VERSION 5.7 ;
  NOWIREEXTENSIONATPIN ON ;
  DIVIDERCHAR "/" ;
  BUSBITCHARS "[]" ;
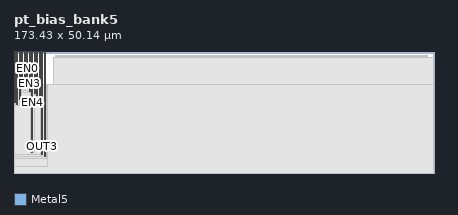
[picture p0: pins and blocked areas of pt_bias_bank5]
MACRO pt_bias_bank5
  CLASS BLOCK ;
  FOREIGN pt_bias_bank5 ;
  ORIGIN -0.300 48.920 ;
  SIZE 173.430 BY 50.140 ;
  PIN VDD
    DIRECTION INOUT ;
    USE POWER ;
    PORT
      LAYER Metal5 ;
        RECT 0.300 -19.620 0.740 1.220 ;
    END
  END VDD
  PIN VSS
    DIRECTION INOUT ;
    USE GROUND ;
    PORT
      LAYER Metal5 ;
        RECT 1.340 -20.520 1.780 1.220 ;
    END
  END VSS
  PIN TRK
    DIRECTION INPUT ;
    USE SIGNAL ;
    ANTENNAGATEAREA 240.000000 ;
    ANTENNADIFFAREA 2.600000 ;
    PORT
      LAYER Metal5 ;
        RECT 2.380 -18.720 2.820 1.220 ;
    END
  END TRK
  PIN EN0
    DIRECTION INPUT ;
    USE SIGNAL ;
    ANTENNAGATEAREA 3.360000 ;
    PORT
      LAYER Metal5 ;
        RECT 3.420 -12.420 3.860 1.220 ;
    END
  END EN0
  PIN EN1
    DIRECTION INPUT ;
    USE SIGNAL ;
    ANTENNAGATEAREA 3.360000 ;
    PORT
      LAYER Metal5 ;
        RECT 4.460 -13.320 4.900 1.220 ;
    END
  END EN1
  PIN EN2
    DIRECTION INPUT ;
    USE SIGNAL ;
    ANTENNAGATEAREA 3.360000 ;
    PORT
      LAYER Metal5 ;
        RECT 5.500 -14.220 5.940 1.220 ;
    END
  END EN2
  PIN EN3
    DIRECTION INPUT ;
    USE SIGNAL ;
    ANTENNAGATEAREA 3.360000 ;
    PORT
      LAYER Metal5 ;
        RECT 6.540 -15.120 6.980 1.220 ;
    END
  END EN3
  PIN EN4
    DIRECTION INPUT ;
    USE SIGNAL ;
    ANTENNAGATEAREA 3.360000 ;
    PORT
      LAYER Metal5 ;
        RECT 7.580 -40.480 8.020 1.220 ;
    END
  END EN4
  PIN OUT0
    DIRECTION OUTPUT ;
    USE SIGNAL ;
    ANTENNADIFFAREA 3.520000 ;
    PORT
      LAYER Metal5 ;
        RECT 8.620 -16.020 9.060 1.220 ;
    END
  END OUT0
  PIN OUT1
    DIRECTION OUTPUT ;
    USE SIGNAL ;
    ANTENNADIFFAREA 3.520000 ;
    PORT
      LAYER Metal5 ;
        RECT 9.660 -16.920 10.100 1.220 ;
    END
  END OUT1
  PIN OUT2
    DIRECTION OUTPUT ;
    USE SIGNAL ;
    ANTENNADIFFAREA 3.520000 ;
    PORT
      LAYER Metal5 ;
        RECT 10.700 -17.820 11.140 1.220 ;
    END
  END OUT2
  PIN OUT3
    DIRECTION OUTPUT ;
    USE SIGNAL ;
    ANTENNADIFFAREA 3.520000 ;
    PORT
      LAYER Metal5 ;
        RECT 11.740 -41.380 12.180 1.220 ;
    END
  END OUT3
  PIN OUT4
    DIRECTION OUTPUT ;
    USE SIGNAL ;
    ANTENNADIFFAREA 3.520000 ;
    PORT
      LAYER Metal5 ;
        RECT 12.780 -42.280 13.220 1.220 ;
    END
  END OUT4
  OBS
      LAYER Nwell ;
        RECT 17.410 -39.220 171.130 -0.600 ;
      LAYER Metal1 ;
        RECT 17.595 -39.120 171.030 -0.785 ;
      LAYER Metal2 ;
        RECT 16.510 -39.120 173.730 -1.360 ;
      LAYER Metal3 ;
        RECT 16.510 -48.920 173.730 -1.360 ;
      LAYER Metal4 ;
        RECT 0.320 -48.920 173.730 -12.360 ;
      LAYER Metal5 ;
        RECT 3.420 -13.920 3.860 -13.020 ;
        RECT 3.420 -14.820 4.900 -13.920 ;
        RECT 3.420 -15.720 5.940 -14.820 ;
        RECT 3.420 -19.320 6.980 -15.720 ;
        RECT 0.300 -19.900 0.380 -19.620 ;
        RECT 0.300 -21.120 0.740 -19.900 ;
        RECT 2.380 -21.120 6.980 -19.320 ;
        RECT 0.300 -41.080 6.980 -21.120 ;
        RECT 8.620 -17.520 9.060 -16.620 ;
        RECT 8.620 -18.420 10.100 -17.520 ;
        RECT 8.620 -41.080 11.140 -18.420 ;
        RECT 0.300 -41.980 11.140 -41.080 ;
        RECT 0.300 -42.880 12.180 -41.980 ;
        RECT 13.820 -42.880 14.260 -12.420 ;
        RECT 0.300 -46.240 14.260 -42.880 ;
  END
END pt_bias_bank5
END LIBRARY

